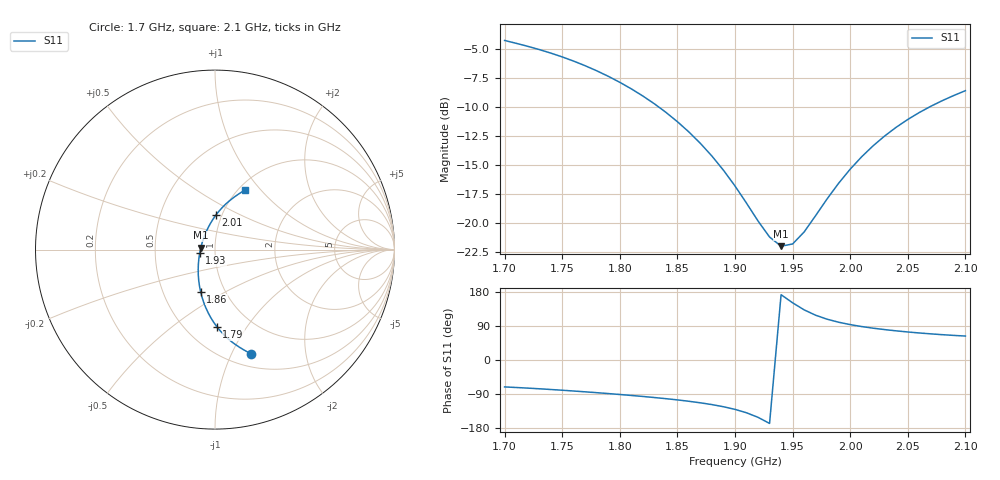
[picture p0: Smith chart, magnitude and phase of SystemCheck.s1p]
! Generated by circuitRF - EM: openEMS
! circuitRF-EM setup: SystemCheck SystemCheck 1.9 GHz
! circuitRF-EM layout: SystemCheck.c3d
! circuitRF-EM written: 2026-10-19 01:14:33Z
! circuitRF-EM geometry: bda383585b075b1e
! circuitRF-EM mesh: c4f8ec3e14ef658c
! circuitRF-EM ports: 84820064c771a764
! circuitRF-EM model: openEMS 0.37.0 (v0.37.0, CSXCAD v0.7.0)
! circuitRF-EM port 1: 'port/1' from 'armLo' to 'armHi', lumped, 50 Ohm
! circuitRF-EM 3D grid: 151 x 109 x 140 = 2304260 cells; smallest cell 901.272 um on z, set by 'armLo' sheet plane at z = 0 um; 'armHi' sheet plane at z = 0 um; 'port/1' port extent at z = 0 um; 'flat/shell' material face at z = 8 mm
! circuitRF-EM 3D openEMS run port 1: dt 1.90223E-12 s (estimate 1.85569E-12 s), 7006 steps, port signals unmeasured (stopped within the pulse) and energy 42.3 dB against 40 dB, stopped by openEMS's energy criterion, converged
! circuitRF-EM 3D dielectric loss fitted at: 1.9 GHz
! circuitRF-EM 3D perfect conductors: armLo, armHi
! circuitRF-EM 3D operating temperature: 20 C
! circuitRF-EM: re-running the EM setup rewrites this file. If circuitRF reports it as stale, the layout's cross-section changed after this file was written.
# GHz S RI R 50
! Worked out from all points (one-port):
!   41 points, 1.7 GHz to 2.1 GHz, reference 50 ohm
!   lowest |S11| = -22.0 dB at 1.94 GHz (marker M1), VSWR 1.17, Z = 42.7 + j0.91 ohm
!   |S11| at or under -10 dB: 1.834 GHz to 2.068 GHz (234.2 MHz wide, 12 % of centre)
!   S11 on the Smith chart (normalised r, x): 1.7 GHz: 0.64, -1.19; 1.79 GHz: 0.70, -0.74; 1.86 GHz: 0.77, -0.38; 1.93 GHz: 0.84, -0.03; 2.01 GHz: 0.94, +0.38; 2.1 GHz: 1.07, +0.83
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1.7  0.1994 -0.5804
1.73  0.1363 -0.5441
1.75  0.0925 -0.513
1.77  0.0498 -0.4749
1.79  0.0106 -0.4299
1.8  -0.00722 -0.4051
1.82  -0.0383 -0.3517
1.83  -0.0514 -0.3234
1.85  -0.0725 -0.2644
1.86  -0.0803 -0.2341
1.87  -0.0863 -0.2034
1.88  -0.0906 -0.1725
1.89  -0.093 -0.1415
1.9  -0.0937 -0.1105
1.92  -0.0898 -0.0492
1.93  -0.0852 -0.019
1.94  -0.079 0.0106
1.95  -0.0712 0.0396
1.96  -0.0618 0.0678
1.98  -0.0386 0.1216
1.99  -0.025 0.1468
2  -0.0101 0.1709
2.01  0.00591 0.1936
2.03  0.0406 0.2346
2.04  0.0588 0.2528
2.06  0.0962 0.2845
2.08  0.1331 0.3106
2.1  0.168 0.3329
